VERSION 5.7 ;
BUSBITCHARS "[]" ;
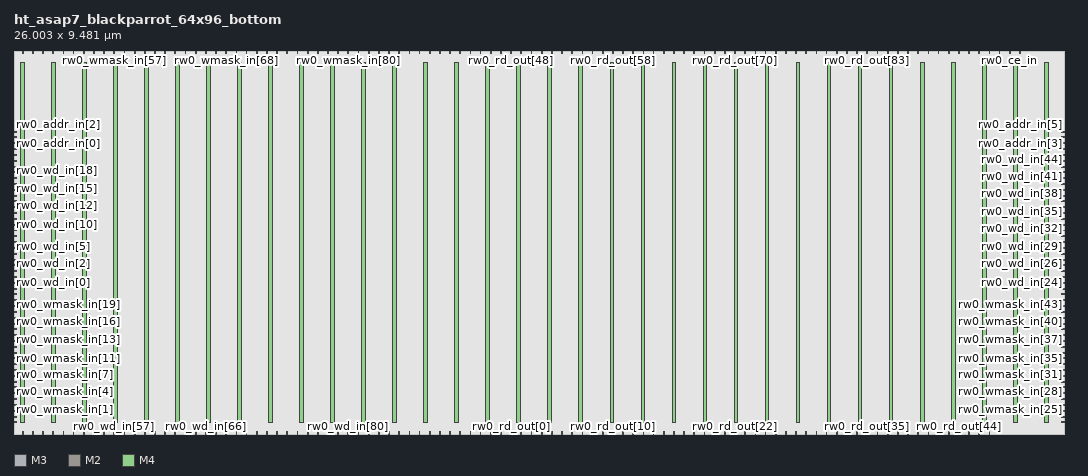
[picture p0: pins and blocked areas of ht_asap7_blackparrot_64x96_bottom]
MACRO ht_asap7_blackparrot_64x96_bottom
  FOREIGN ht_asap7_blackparrot_64x96_bottom 0 0 ;
  SYMMETRY X Y R90 ;
  SIZE 26.003 BY 9.481 ;
  CLASS COVER ;
  PIN rw0_wmask_in[0]
    DIRECTION INPUT ;
    USE SIGNAL ;
    SHAPE ABUTMENT ;
    PORT
      LAYER M3 ;
      RECT 0.000 0.276 0.072 0.300 ;
    END
  END rw0_wmask_in[0]
  PIN rw0_wmask_in[1]
    DIRECTION INPUT ;
    USE SIGNAL ;
    SHAPE ABUTMENT ;
    PORT
      LAYER M3 ;
      RECT 0.000 0.420 0.072 0.444 ;
    END
  END rw0_wmask_in[1]
  PIN rw0_wmask_in[2]
    DIRECTION INPUT ;
    USE SIGNAL ;
    SHAPE ABUTMENT ;
    PORT
      LAYER M3 ;
      RECT 0.000 0.564 0.072 0.588 ;
    END
  END rw0_wmask_in[2]
  PIN rw0_wmask_in[3]
    DIRECTION INPUT ;
    USE SIGNAL ;
    SHAPE ABUTMENT ;
    PORT
      LAYER M3 ;
      RECT 0.000 0.708 0.072 0.732 ;
    END
  END rw0_wmask_in[3]
  PIN rw0_wmask_in[4]
    DIRECTION INPUT ;
    USE SIGNAL ;
    SHAPE ABUTMENT ;
    PORT
      LAYER M3 ;
      RECT 0.000 0.852 0.072 0.876 ;
    END
  END rw0_wmask_in[4]
  PIN rw0_wmask_in[5]
    DIRECTION INPUT ;
    USE SIGNAL ;
    SHAPE ABUTMENT ;
    PORT
      LAYER M3 ;
      RECT 0.000 0.996 0.072 1.020 ;
    END
  END rw0_wmask_in[5]
  PIN rw0_wmask_in[6]
    DIRECTION INPUT ;
    USE SIGNAL ;
    SHAPE ABUTMENT ;
    PORT
      LAYER M3 ;
      RECT 0.000 1.140 0.072 1.164 ;
    END
  END rw0_wmask_in[6]
  PIN rw0_wmask_in[7]
    DIRECTION INPUT ;
    USE SIGNAL ;
    SHAPE ABUTMENT ;
    PORT
      LAYER M3 ;
      RECT 0.000 1.284 0.072 1.308 ;
    END
  END rw0_wmask_in[7]
  PIN rw0_wmask_in[8]
    DIRECTION INPUT ;
    USE SIGNAL ;
    SHAPE ABUTMENT ;
    PORT
      LAYER M3 ;
      RECT 0.000 1.428 0.072 1.452 ;
    END
  END rw0_wmask_in[8]
  PIN rw0_wmask_in[9]
    DIRECTION INPUT ;
    USE SIGNAL ;
    SHAPE ABUTMENT ;
    PORT
      LAYER M3 ;
      RECT 0.000 1.572 0.072 1.596 ;
    END
  END rw0_wmask_in[9]
  PIN rw0_wmask_in[10]
    DIRECTION INPUT ;
    USE SIGNAL ;
    SHAPE ABUTMENT ;
    PORT
      LAYER M3 ;
      RECT 0.000 1.716 0.072 1.740 ;
    END
  END rw0_wmask_in[10]
  PIN rw0_wmask_in[11]
    DIRECTION INPUT ;
    USE SIGNAL ;
    SHAPE ABUTMENT ;
    PORT
      LAYER M3 ;
      RECT 0.000 1.860 0.072 1.884 ;
    END
  END rw0_wmask_in[11]
  PIN rw0_wmask_in[12]
    DIRECTION INPUT ;
    USE SIGNAL ;
    SHAPE ABUTMENT ;
    PORT
      LAYER M3 ;
      RECT 0.000 2.004 0.072 2.028 ;
    END
  END rw0_wmask_in[12]
  PIN rw0_wmask_in[13]
    DIRECTION INPUT ;
    USE SIGNAL ;
    SHAPE ABUTMENT ;
    PORT
      LAYER M3 ;
      RECT 0.000 2.148 0.072 2.172 ;
    END
  END rw0_wmask_in[13]
  PIN rw0_wmask_in[14]
    DIRECTION INPUT ;
    USE SIGNAL ;
    SHAPE ABUTMENT ;
    PORT
      LAYER M3 ;
      RECT 0.000 2.292 0.072 2.316 ;
    END
  END rw0_wmask_in[14]
  PIN rw0_wmask_in[15]
    DIRECTION INPUT ;
    USE SIGNAL ;
    SHAPE ABUTMENT ;
    PORT
      LAYER M3 ;
      RECT 0.000 2.436 0.072 2.460 ;
    END
  END rw0_wmask_in[15]
  PIN rw0_wmask_in[16]
    DIRECTION INPUT ;
    USE SIGNAL ;
    SHAPE ABUTMENT ;
    PORT
      LAYER M3 ;
      RECT 0.000 2.580 0.072 2.604 ;
    END
  END rw0_wmask_in[16]
  PIN rw0_wmask_in[17]
    DIRECTION INPUT ;
    USE SIGNAL ;
    SHAPE ABUTMENT ;
    PORT
      LAYER M3 ;
      RECT 0.000 2.724 0.072 2.748 ;
    END
  END rw0_wmask_in[17]
  PIN rw0_wmask_in[18]
    DIRECTION INPUT ;
    USE SIGNAL ;
    SHAPE ABUTMENT ;
    PORT
      LAYER M3 ;
      RECT 0.000 2.868 0.072 2.892 ;
    END
  END rw0_wmask_in[18]
  PIN rw0_wmask_in[19]
    DIRECTION INPUT ;
    USE SIGNAL ;
    SHAPE ABUTMENT ;
    PORT
      LAYER M3 ;
      RECT 0.000 3.012 0.072 3.036 ;
    END
  END rw0_wmask_in[19]
  PIN rw0_wmask_in[20]
    DIRECTION INPUT ;
    USE SIGNAL ;
    SHAPE ABUTMENT ;
    PORT
      LAYER M3 ;
      RECT 0.000 3.156 0.072 3.180 ;
    END
  END rw0_wmask_in[20]
  PIN rw0_wmask_in[21]
    DIRECTION INPUT ;
    USE SIGNAL ;
    SHAPE ABUTMENT ;
    PORT
      LAYER M3 ;
      RECT 0.000 3.300 0.072 3.324 ;
    END
  END rw0_wmask_in[21]
  PIN rw0_wmask_in[22]
    DIRECTION INPUT ;
    USE SIGNAL ;
    SHAPE ABUTMENT ;
    PORT
      LAYER M3 ;
      RECT 0.000 3.444 0.072 3.468 ;
    END
  END rw0_wmask_in[22]
  PIN rw0_wmask_in[23]
    DIRECTION INPUT ;
    USE SIGNAL ;
    SHAPE ABUTMENT ;
    PORT
      LAYER M3 ;
      RECT 0.000 3.588 0.072 3.612 ;
    END
  END rw0_wmask_in[23]
  PIN rw0_wmask_in[24]
    DIRECTION INPUT ;
    USE SIGNAL ;
    SHAPE ABUTMENT ;
    PORT
      LAYER M3 ;
      RECT 25.931 0.276 26.003 0.300 ;
    END
  END rw0_wmask_in[24]
  PIN rw0_wmask_in[25]
    DIRECTION INPUT ;
    USE SIGNAL ;
    SHAPE ABUTMENT ;
    PORT
      LAYER M3 ;
      RECT 25.931 0.420 26.003 0.444 ;
    END
  END rw0_wmask_in[25]
  PIN rw0_wmask_in[26]
    DIRECTION INPUT ;
    USE SIGNAL ;
    SHAPE ABUTMENT ;
    PORT
      LAYER M3 ;
      RECT 25.931 0.564 26.003 0.588 ;
    END
  END rw0_wmask_in[26]
  PIN rw0_wmask_in[27]
    DIRECTION INPUT ;
    USE SIGNAL ;
    SHAPE ABUTMENT ;
    PORT
      LAYER M3 ;
      RECT 25.931 0.708 26.003 0.732 ;
    END
  END rw0_wmask_in[27]
  PIN rw0_wmask_in[28]
    DIRECTION INPUT ;
    USE SIGNAL ;
    SHAPE ABUTMENT ;
    PORT
      LAYER M3 ;
      RECT 25.931 0.852 26.003 0.876 ;
    END
  END rw0_wmask_in[28]
  PIN rw0_wmask_in[29]
    DIRECTION INPUT ;
    USE SIGNAL ;
    SHAPE ABUTMENT ;
    PORT
      LAYER M3 ;
      RECT 25.931 0.996 26.003 1.020 ;
    END
  END rw0_wmask_in[29]
  PIN rw0_wmask_in[30]
    DIRECTION INPUT ;
    USE SIGNAL ;
    SHAPE ABUTMENT ;
    PORT
      LAYER M3 ;
      RECT 25.931 1.140 26.003 1.164 ;
    END
  END rw0_wmask_in[30]
  PIN rw0_wmask_in[31]
    DIRECTION INPUT ;
    USE SIGNAL ;
    SHAPE ABUTMENT ;
    PORT
      LAYER M3 ;
      RECT 25.931 1.284 26.003 1.308 ;
    END
  END rw0_wmask_in[31]
  PIN rw0_wmask_in[32]
    DIRECTION INPUT ;
    USE SIGNAL ;
    SHAPE ABUTMENT ;
    PORT
      LAYER M3 ;
      RECT 25.931 1.428 26.003 1.452 ;
    END
  END rw0_wmask_in[32]
  PIN rw0_wmask_in[33]
    DIRECTION INPUT ;
    USE SIGNAL ;
    SHAPE ABUTMENT ;
    PORT
      LAYER M3 ;
      RECT 25.931 1.572 26.003 1.596 ;
    END
  END rw0_wmask_in[33]
  PIN rw0_wmask_in[34]
    DIRECTION INPUT ;
    USE SIGNAL ;
    SHAPE ABUTMENT ;
    PORT
      LAYER M3 ;
      RECT 25.931 1.716 26.003 1.740 ;
    END
  END rw0_wmask_in[34]
  PIN rw0_wmask_in[35]
    DIRECTION INPUT ;
    USE SIGNAL ;
    SHAPE ABUTMENT ;
    PORT
      LAYER M3 ;
      RECT 25.931 1.860 26.003 1.884 ;
    END
  END rw0_wmask_in[35]
  PIN rw0_wmask_in[36]
    DIRECTION INPUT ;
    USE SIGNAL ;
    SHAPE ABUTMENT ;
    PORT
      LAYER M3 ;
      RECT 25.931 2.004 26.003 2.028 ;
    END
  END rw0_wmask_in[36]
  PIN rw0_wmask_in[37]
    DIRECTION INPUT ;
    USE SIGNAL ;
    SHAPE ABUTMENT ;
    PORT
      LAYER M3 ;
      RECT 25.931 2.148 26.003 2.172 ;
    END
  END rw0_wmask_in[37]
  PIN rw0_wmask_in[38]
    DIRECTION INPUT ;
    USE SIGNAL ;
    SHAPE ABUTMENT ;
    PORT
      LAYER M3 ;
      RECT 25.931 2.292 26.003 2.316 ;
    END
  END rw0_wmask_in[38]
  PIN rw0_wmask_in[39]
    DIRECTION INPUT ;
    USE SIGNAL ;
    SHAPE ABUTMENT ;
    PORT
      LAYER M3 ;
      RECT 25.931 2.436 26.003 2.460 ;
    END
  END rw0_wmask_in[39]
  PIN rw0_wmask_in[40]
    DIRECTION INPUT ;
    USE SIGNAL ;
    SHAPE ABUTMENT ;
    PORT
      LAYER M3 ;
      RECT 25.931 2.580 26.003 2.604 ;
    END
  END rw0_wmask_in[40]
  PIN rw0_wmask_in[41]
    DIRECTION INPUT ;
    USE SIGNAL ;
    SHAPE ABUTMENT ;
    PORT
      LAYER M3 ;
      RECT 25.931 2.724 26.003 2.748 ;
    END
  END rw0_wmask_in[41]
  PIN rw0_wmask_in[42]
    DIRECTION INPUT ;
    USE SIGNAL ;
    SHAPE ABUTMENT ;
    PORT
      LAYER M3 ;
      RECT 25.931 2.868 26.003 2.892 ;
    END
  END rw0_wmask_in[42]
  PIN rw0_wmask_in[43]
    DIRECTION INPUT ;
    USE SIGNAL ;
    SHAPE ABUTMENT ;
    PORT
      LAYER M3 ;
      RECT 25.931 3.012 26.003 3.036 ;
    END
  END rw0_wmask_in[43]
  PIN rw0_wmask_in[44]
    DIRECTION INPUT ;
    USE SIGNAL ;
    SHAPE ABUTMENT ;
    PORT
      LAYER M3 ;
      RECT 25.931 3.156 26.003 3.180 ;
    END
  END rw0_wmask_in[44]
  PIN rw0_wmask_in[45]
    DIRECTION INPUT ;
    USE SIGNAL ;
    SHAPE ABUTMENT ;
    PORT
      LAYER M3 ;
      RECT 25.931 3.300 26.003 3.324 ;
    END
  END rw0_wmask_in[45]
  PIN rw0_wmask_in[46]
    DIRECTION INPUT ;
    USE SIGNAL ;
    SHAPE ABUTMENT ;
    PORT
      LAYER M3 ;
      RECT 25.931 3.444 26.003 3.468 ;
    END
  END rw0_wmask_in[46]
  PIN rw0_wmask_in[47]
    DIRECTION INPUT ;
    USE SIGNAL ;
    SHAPE ABUTMENT ;
    PORT
      LAYER M3 ;
      RECT 25.931 3.588 26.003 3.612 ;
    END
  END rw0_wmask_in[47]
  PIN rw0_wmask_in[48]
    DIRECTION INPUT ;
    USE SIGNAL ;
    SHAPE ABUTMENT ;
    PORT
      LAYER M2 ;
      RECT 0.207 9.427 0.225 9.481 ;
    END
  END rw0_wmask_in[48]
  PIN rw0_wmask_in[49]
    DIRECTION INPUT ;
    USE SIGNAL ;
    SHAPE ABUTMENT ;
    PORT
      LAYER M2 ;
      RECT 0.459 9.427 0.477 9.481 ;
    END
  END rw0_wmask_in[49]
  PIN rw0_wmask_in[50]
    DIRECTION INPUT ;
    USE SIGNAL ;
    SHAPE ABUTMENT ;
    PORT
      LAYER M2 ;
      RECT 0.711 9.427 0.729 9.481 ;
    END
  END rw0_wmask_in[50]
  PIN rw0_wmask_in[51]
    DIRECTION INPUT ;
    USE SIGNAL ;
    SHAPE ABUTMENT ;
    PORT
      LAYER M2 ;
      RECT 0.963 9.427 0.981 9.481 ;
    END
  END rw0_wmask_in[51]
  PIN rw0_wmask_in[52]
    DIRECTION INPUT ;
    USE SIGNAL ;
    SHAPE ABUTMENT ;
    PORT
      LAYER M2 ;
      RECT 1.215 9.427 1.233 9.481 ;
    END
  END rw0_wmask_in[52]
  PIN rw0_wmask_in[53]
    DIRECTION INPUT ;
    USE SIGNAL ;
    SHAPE ABUTMENT ;
    PORT
      LAYER M2 ;
      RECT 1.467 9.427 1.485 9.481 ;
    END
  END rw0_wmask_in[53]
  PIN rw0_wmask_in[54]
    DIRECTION INPUT ;
    USE SIGNAL ;
    SHAPE ABUTMENT ;
    PORT
      LAYER M2 ;
      RECT 1.719 9.427 1.737 9.481 ;
    END
  END rw0_wmask_in[54]
  PIN rw0_wmask_in[55]
    DIRECTION INPUT ;
    USE SIGNAL ;
    SHAPE ABUTMENT ;
    PORT
      LAYER M2 ;
      RECT 1.971 9.427 1.989 9.481 ;
    END
  END rw0_wmask_in[55]
  PIN rw0_wmask_in[56]
    DIRECTION INPUT ;
    USE SIGNAL ;
    SHAPE ABUTMENT ;
    PORT
      LAYER M2 ;
      RECT 2.223 9.427 2.241 9.481 ;
    END
  END rw0_wmask_in[56]
  PIN rw0_wmask_in[57]
    DIRECTION INPUT ;
    USE SIGNAL ;
    SHAPE ABUTMENT ;
    PORT
      LAYER M2 ;
      RECT 2.475 9.427 2.493 9.481 ;
    END
  END rw0_wmask_in[57]
  PIN rw0_wmask_in[58]
    DIRECTION INPUT ;
    USE SIGNAL ;
    SHAPE ABUTMENT ;
    PORT
      LAYER M2 ;
      RECT 2.727 9.427 2.745 9.481 ;
    END
  END rw0_wmask_in[58]
  PIN rw0_wmask_in[59]
    DIRECTION INPUT ;
    USE SIGNAL ;
    SHAPE ABUTMENT ;
    PORT
      LAYER M2 ;
      RECT 2.979 9.427 2.997 9.481 ;
    END
  END rw0_wmask_in[59]
  PIN rw0_wmask_in[60]
    DIRECTION INPUT ;
    USE SIGNAL ;
    SHAPE ABUTMENT ;
    PORT
      LAYER M2 ;
      RECT 3.231 9.427 3.249 9.481 ;
    END
  END rw0_wmask_in[60]
  PIN rw0_wmask_in[61]
    DIRECTION INPUT ;
    USE SIGNAL ;
    SHAPE ABUTMENT ;
    PORT
      LAYER M2 ;
      RECT 3.483 9.427 3.501 9.481 ;
    END
  END rw0_wmask_in[61]
  PIN rw0_wmask_in[62]
    DIRECTION INPUT ;
    USE SIGNAL ;
    SHAPE ABUTMENT ;
    PORT
      LAYER M2 ;
      RECT 3.735 9.427 3.753 9.481 ;
    END
  END rw0_wmask_in[62]
  PIN rw0_wmask_in[63]
    DIRECTION INPUT ;
    USE SIGNAL ;
    SHAPE ABUTMENT ;
    PORT
      LAYER M2 ;
      RECT 3.987 9.427 4.005 9.481 ;
    END
  END rw0_wmask_in[63]
  PIN rw0_wmask_in[64]
    DIRECTION INPUT ;
    USE SIGNAL ;
    SHAPE ABUTMENT ;
    PORT
      LAYER M2 ;
      RECT 4.239 9.427 4.257 9.481 ;
    END
  END rw0_wmask_in[64]
  PIN rw0_wmask_in[65]
    DIRECTION INPUT ;
    USE SIGNAL ;
    SHAPE ABUTMENT ;
    PORT
      LAYER M2 ;
      RECT 4.491 9.427 4.509 9.481 ;
    END
  END rw0_wmask_in[65]
  PIN rw0_wmask_in[66]
    DIRECTION INPUT ;
    USE SIGNAL ;
    SHAPE ABUTMENT ;
    PORT
      LAYER M2 ;
      RECT 4.743 9.427 4.761 9.481 ;
    END
  END rw0_wmask_in[66]
  PIN rw0_wmask_in[67]
    DIRECTION INPUT ;
    USE SIGNAL ;
    SHAPE ABUTMENT ;
    PORT
      LAYER M2 ;
      RECT 4.995 9.427 5.013 9.481 ;
    END
  END rw0_wmask_in[67]
  PIN rw0_wmask_in[68]
    DIRECTION INPUT ;
    USE SIGNAL ;
    SHAPE ABUTMENT ;
    PORT
      LAYER M2 ;
      RECT 5.247 9.427 5.265 9.481 ;
    END
  END rw0_wmask_in[68]
  PIN rw0_wmask_in[69]
    DIRECTION INPUT ;
    USE SIGNAL ;
    SHAPE ABUTMENT ;
    PORT
      LAYER M2 ;
      RECT 5.499 9.427 5.517 9.481 ;
    END
  END rw0_wmask_in[69]
  PIN rw0_wmask_in[70]
    DIRECTION INPUT ;
    USE SIGNAL ;
    SHAPE ABUTMENT ;
    PORT
      LAYER M2 ;
      RECT 5.751 9.427 5.769 9.481 ;
    END
  END rw0_wmask_in[70]
  PIN rw0_wmask_in[71]
    DIRECTION INPUT ;
    USE SIGNAL ;
    SHAPE ABUTMENT ;
    PORT
      LAYER M2 ;
      RECT 6.003 9.427 6.021 9.481 ;
    END
  END rw0_wmask_in[71]
  PIN rw0_wmask_in[72]
    DIRECTION INPUT ;
    USE SIGNAL ;
    SHAPE ABUTMENT ;
    PORT
      LAYER M2 ;
      RECT 6.255 9.427 6.273 9.481 ;
    END
  END rw0_wmask_in[72]
  PIN rw0_wmask_in[73]
    DIRECTION INPUT ;
    USE SIGNAL ;
    SHAPE ABUTMENT ;
    PORT
      LAYER M2 ;
      RECT 6.507 9.427 6.525 9.481 ;
    END
  END rw0_wmask_in[73]
  PIN rw0_wmask_in[74]
    DIRECTION INPUT ;
    USE SIGNAL ;
    SHAPE ABUTMENT ;
    PORT
      LAYER M2 ;
      RECT 6.759 9.427 6.777 9.481 ;
    END
  END rw0_wmask_in[74]
  PIN rw0_wmask_in[75]
    DIRECTION INPUT ;
    USE SIGNAL ;
    SHAPE ABUTMENT ;
    PORT
      LAYER M2 ;
      RECT 7.011 9.427 7.029 9.481 ;
    END
  END rw0_wmask_in[75]
  PIN rw0_wmask_in[76]
    DIRECTION INPUT ;
    USE SIGNAL ;
    SHAPE ABUTMENT ;
    PORT
      LAYER M2 ;
      RECT 7.263 9.427 7.281 9.481 ;
    END
  END rw0_wmask_in[76]
  PIN rw0_wmask_in[77]
    DIRECTION INPUT ;
    USE SIGNAL ;
    SHAPE ABUTMENT ;
    PORT
      LAYER M2 ;
      RECT 7.515 9.427 7.533 9.481 ;
    END
  END rw0_wmask_in[77]
  PIN rw0_wmask_in[78]
    DIRECTION INPUT ;
    USE SIGNAL ;
    SHAPE ABUTMENT ;
    PORT
      LAYER M2 ;
      RECT 7.767 9.427 7.785 9.481 ;
    END
  END rw0_wmask_in[78]
  PIN rw0_wmask_in[79]
    DIRECTION INPUT ;
    USE SIGNAL ;
    SHAPE ABUTMENT ;
    PORT
      LAYER M2 ;
      RECT 8.019 9.427 8.037 9.481 ;
    END
  END rw0_wmask_in[79]
  PIN rw0_wmask_in[80]
    DIRECTION INPUT ;
    USE SIGNAL ;
    SHAPE ABUTMENT ;
    PORT
      LAYER M2 ;
      RECT 8.271 9.427 8.289 9.481 ;
    END
  END rw0_wmask_in[80]
  PIN rw0_wmask_in[81]
    DIRECTION INPUT ;
    USE SIGNAL ;
    SHAPE ABUTMENT ;
    PORT
      LAYER M2 ;
      RECT 8.523 9.427 8.541 9.481 ;
    END
  END rw0_wmask_in[81]
  PIN rw0_wmask_in[82]
    DIRECTION INPUT ;
    USE SIGNAL ;
    SHAPE ABUTMENT ;
    PORT
      LAYER M2 ;
      RECT 8.775 9.427 8.793 9.481 ;
    END
  END rw0_wmask_in[82]
  PIN rw0_wmask_in[83]
    DIRECTION INPUT ;
    USE SIGNAL ;
    SHAPE ABUTMENT ;
    PORT
      LAYER M2 ;
      RECT 9.027 9.427 9.045 9.481 ;
    END
  END rw0_wmask_in[83]
  PIN rw0_wmask_in[84]
    DIRECTION INPUT ;
    USE SIGNAL ;
    SHAPE ABUTMENT ;
    PORT
      LAYER M2 ;
      RECT 9.279 9.427 9.297 9.481 ;
    END
  END rw0_wmask_in[84]
  PIN rw0_wmask_in[85]
    DIRECTION INPUT ;
    USE SIGNAL ;
    SHAPE ABUTMENT ;
    PORT
      LAYER M2 ;
      RECT 9.531 9.427 9.549 9.481 ;
    END
  END rw0_wmask_in[85]
  PIN rw0_wmask_in[86]
    DIRECTION INPUT ;
    USE SIGNAL ;
    SHAPE ABUTMENT ;
    PORT
      LAYER M2 ;
      RECT 9.783 9.427 9.801 9.481 ;
    END
  END rw0_wmask_in[86]
  PIN rw0_wmask_in[87]
    DIRECTION INPUT ;
    USE SIGNAL ;
    SHAPE ABUTMENT ;
    PORT
      LAYER M2 ;
      RECT 10.035 9.427 10.053 9.481 ;
    END
  END rw0_wmask_in[87]
  PIN rw0_wmask_in[88]
    DIRECTION INPUT ;
    USE SIGNAL ;
    SHAPE ABUTMENT ;
    PORT
      LAYER M2 ;
      RECT 10.287 9.427 10.305 9.481 ;
    END
  END rw0_wmask_in[88]
  PIN rw0_wmask_in[89]
    DIRECTION INPUT ;
    USE SIGNAL ;
    SHAPE ABUTMENT ;
    PORT
      LAYER M2 ;
      RECT 10.539 9.427 10.557 9.481 ;
    END
  END rw0_wmask_in[89]
  PIN rw0_wmask_in[90]
    DIRECTION INPUT ;
    USE SIGNAL ;
    SHAPE ABUTMENT ;
    PORT
      LAYER M2 ;
      RECT 10.791 9.427 10.809 9.481 ;
    END
  END rw0_wmask_in[90]
  PIN rw0_wmask_in[91]
    DIRECTION INPUT ;
    USE SIGNAL ;
    SHAPE ABUTMENT ;
    PORT
      LAYER M2 ;
      RECT 11.043 9.427 11.061 9.481 ;
    END
  END rw0_wmask_in[91]
  PIN rw0_wmask_in[92]
    DIRECTION INPUT ;
    USE SIGNAL ;
    SHAPE ABUTMENT ;
    PORT
      LAYER M2 ;
      RECT 11.295 9.427 11.313 9.481 ;
    END
  END rw0_wmask_in[92]
  PIN rw0_wmask_in[93]
    DIRECTION INPUT ;
    USE SIGNAL ;
    SHAPE ABUTMENT ;
    PORT
      LAYER M2 ;
      RECT 11.547 9.427 11.565 9.481 ;
    END
  END rw0_wmask_in[93]
  PIN rw0_wmask_in[94]
    DIRECTION INPUT ;
    USE SIGNAL ;
    SHAPE ABUTMENT ;
    PORT
      LAYER M2 ;
      RECT 11.799 9.427 11.817 9.481 ;
    END
  END rw0_wmask_in[94]
  PIN rw0_wmask_in[95]
    DIRECTION INPUT ;
    USE SIGNAL ;
    SHAPE ABUTMENT ;
    PORT
      LAYER M2 ;
      RECT 12.051 9.427 12.069 9.481 ;
    END
  END rw0_wmask_in[95]
  PIN rw0_wd_in[0]
    DIRECTION INPUT ;
    USE SIGNAL ;
    SHAPE ABUTMENT ;
    PORT
      LAYER M3 ;
      RECT 0.000 3.732 0.072 3.756 ;
    END
  END rw0_wd_in[0]
  PIN rw0_wd_in[1]
    DIRECTION INPUT ;
    USE SIGNAL ;
    SHAPE ABUTMENT ;
    PORT
      LAYER M3 ;
      RECT 0.000 3.876 0.072 3.900 ;
    END
  END rw0_wd_in[1]
  PIN rw0_wd_in[2]
    DIRECTION INPUT ;
    USE SIGNAL ;
    SHAPE ABUTMENT ;
    PORT
      LAYER M3 ;
      RECT 0.000 4.020 0.072 4.044 ;
    END
  END rw0_wd_in[2]
  PIN rw0_wd_in[3]
    DIRECTION INPUT ;
    USE SIGNAL ;
    SHAPE ABUTMENT ;
    PORT
      LAYER M3 ;
      RECT 0.000 4.164 0.072 4.188 ;
    END
  END rw0_wd_in[3]
  PIN rw0_wd_in[4]
    DIRECTION INPUT ;
    USE SIGNAL ;
    SHAPE ABUTMENT ;
    PORT
      LAYER M3 ;
      RECT 0.000 4.308 0.072 4.332 ;
    END
  END rw0_wd_in[4]
  PIN rw0_wd_in[5]
    DIRECTION INPUT ;
    USE SIGNAL ;
    SHAPE ABUTMENT ;
    PORT
      LAYER M3 ;
      RECT 0.000 4.452 0.072 4.476 ;
    END
  END rw0_wd_in[5]
  PIN rw0_wd_in[6]
    DIRECTION INPUT ;
    USE SIGNAL ;
    SHAPE ABUTMENT ;
    PORT
      LAYER M3 ;
      RECT 0.000 4.596 0.072 4.620 ;
    END
  END rw0_wd_in[6]
  PIN rw0_wd_in[7]
    DIRECTION INPUT ;
    USE SIGNAL ;
    SHAPE ABUTMENT ;
    PORT
      LAYER M3 ;
      RECT 0.000 4.740 0.072 4.764 ;
    END
  END rw0_wd_in[7]
  PIN rw0_wd_in[8]
    DIRECTION INPUT ;
    USE SIGNAL ;
    SHAPE ABUTMENT ;
    PORT
      LAYER M3 ;
      RECT 0.000 4.884 0.072 4.908 ;
    END
  END rw0_wd_in[8]
  PIN rw0_wd_in[9]
    DIRECTION INPUT ;
    USE SIGNAL ;
    SHAPE ABUTMENT ;
    PORT
      LAYER M3 ;
      RECT 0.000 5.028 0.072 5.052 ;
    END
  END rw0_wd_in[9]
  PIN rw0_wd_in[10]
    DIRECTION INPUT ;
    USE SIGNAL ;
    SHAPE ABUTMENT ;
    PORT
      LAYER M3 ;
      RECT 0.000 5.172 0.072 5.196 ;
    END
  END rw0_wd_in[10]
  PIN rw0_wd_in[11]
    DIRECTION INPUT ;
    USE SIGNAL ;
    SHAPE ABUTMENT ;
    PORT
      LAYER M3 ;
      RECT 0.000 5.316 0.072 5.340 ;
    END
  END rw0_wd_in[11]
  PIN rw0_wd_in[12]
    DIRECTION INPUT ;
    USE SIGNAL ;
    SHAPE ABUTMENT ;
    PORT
      LAYER M3 ;
      RECT 0.000 5.460 0.072 5.484 ;
    END
  END rw0_wd_in[12]
  PIN rw0_wd_in[13]
    DIRECTION INPUT ;
    USE SIGNAL ;
    SHAPE ABUTMENT ;
    PORT
      LAYER M3 ;
      RECT 0.000 5.604 0.072 5.628 ;
    END
  END rw0_wd_in[13]
  PIN rw0_wd_in[14]
    DIRECTION INPUT ;
    USE SIGNAL ;
    SHAPE ABUTMENT ;
    PORT
      LAYER M3 ;
      RECT 0.000 5.748 0.072 5.772 ;
    END
  END rw0_wd_in[14]
  PIN rw0_wd_in[15]
    DIRECTION INPUT ;
    USE SIGNAL ;
    SHAPE ABUTMENT ;
    PORT
      LAYER M3 ;
      RECT 0.000 5.892 0.072 5.916 ;
    END
  END rw0_wd_in[15]
  PIN rw0_wd_in[16]
    DIRECTION INPUT ;
    USE SIGNAL ;
    SHAPE ABUTMENT ;
    PORT
      LAYER M3 ;
      RECT 0.000 6.036 0.072 6.060 ;
    END
  END rw0_wd_in[16]
  PIN rw0_wd_in[17]
    DIRECTION INPUT ;
    USE SIGNAL ;
    SHAPE ABUTMENT ;
    PORT
      LAYER M3 ;
      RECT 0.000 6.180 0.072 6.204 ;
    END
  END rw0_wd_in[17]
  PIN rw0_wd_in[18]
    DIRECTION INPUT ;
    USE SIGNAL ;
    SHAPE ABUTMENT ;
    PORT
      LAYER M3 ;
      RECT 0.000 6.324 0.072 6.348 ;
    END
  END rw0_wd_in[18]
  PIN rw0_wd_in[19]
    DIRECTION INPUT ;
    USE SIGNAL ;
    SHAPE ABUTMENT ;
    PORT
      LAYER M3 ;
      RECT 0.000 6.468 0.072 6.492 ;
    END
  END rw0_wd_in[19]
  PIN rw0_wd_in[20]
    DIRECTION INPUT ;
    USE SIGNAL ;
    SHAPE ABUTMENT ;
    PORT
      LAYER M3 ;
      RECT 0.000 6.612 0.072 6.636 ;
    END
  END rw0_wd_in[20]
  PIN rw0_wd_in[21]
    DIRECTION INPUT ;
    USE SIGNAL ;
    SHAPE ABUTMENT ;
    PORT
      LAYER M3 ;
      RECT 0.000 6.756 0.072 6.780 ;
    END
  END rw0_wd_in[21]
  PIN rw0_wd_in[22]
    DIRECTION INPUT ;
    USE SIGNAL ;
    SHAPE ABUTMENT ;
    PORT
      LAYER M3 ;
      RECT 0.000 6.900 0.072 6.924 ;
    END
  END rw0_wd_in[22]
  PIN rw0_wd_in[23]
    DIRECTION INPUT ;
    USE SIGNAL ;
    SHAPE ABUTMENT ;
    PORT
      LAYER M3 ;
      RECT 0.000 7.044 0.072 7.068 ;
    END
  END rw0_wd_in[23]
  PIN rw0_wd_in[24]
    DIRECTION INPUT ;
    USE SIGNAL ;
    SHAPE ABUTMENT ;
    PORT
      LAYER M3 ;
      RECT 25.931 3.732 26.003 3.756 ;
    END
  END rw0_wd_in[24]
  PIN rw0_wd_in[25]
    DIRECTION INPUT ;
    USE SIGNAL ;
    SHAPE ABUTMENT ;
    PORT
      LAYER M3 ;
      RECT 25.931 3.876 26.003 3.900 ;
    END
  END rw0_wd_in[25]
  PIN rw0_wd_in[26]
    DIRECTION INPUT ;
    USE SIGNAL ;
    SHAPE ABUTMENT ;
    PORT
      LAYER M3 ;
      RECT 25.931 4.020 26.003 4.044 ;
    END
  END rw0_wd_in[26]
  PIN rw0_wd_in[27]
    DIRECTION INPUT ;
    USE SIGNAL ;
    SHAPE ABUTMENT ;
    PORT
      LAYER M3 ;
      RECT 25.931 4.164 26.003 4.188 ;
    END
  END rw0_wd_in[27]
  PIN rw0_wd_in[28]
    DIRECTION INPUT ;
    USE SIGNAL ;
    SHAPE ABUTMENT ;
    PORT
      LAYER M3 ;
      RECT 25.931 4.308 26.003 4.332 ;
    END
  END rw0_wd_in[28]
  PIN rw0_wd_in[29]
    DIRECTION INPUT ;
    USE SIGNAL ;
    SHAPE ABUTMENT ;
    PORT
      LAYER M3 ;
      RECT 25.931 4.452 26.003 4.476 ;
    END
  END rw0_wd_in[29]
  PIN rw0_wd_in[30]
    DIRECTION INPUT ;
    USE SIGNAL ;
    SHAPE ABUTMENT ;
    PORT
      LAYER M3 ;
      RECT 25.931 4.596 26.003 4.620 ;
    END
  END rw0_wd_in[30]
  PIN rw0_wd_in[31]
    DIRECTION INPUT ;
    USE SIGNAL ;
    SHAPE ABUTMENT ;
    PORT
      LAYER M3 ;
      RECT 25.931 4.740 26.003 4.764 ;
    END
  END rw0_wd_in[31]
  PIN rw0_wd_in[32]
    DIRECTION INPUT ;
    USE SIGNAL ;
    SHAPE ABUTMENT ;
    PORT
      LAYER M3 ;
      RECT 25.931 4.884 26.003 4.908 ;
    END
  END rw0_wd_in[32]
  PIN rw0_wd_in[33]
    DIRECTION INPUT ;
    USE SIGNAL ;
    SHAPE ABUTMENT ;
    PORT
      LAYER M3 ;
      RECT 25.931 5.028 26.003 5.052 ;
    END
  END rw0_wd_in[33]
  PIN rw0_wd_in[34]
    DIRECTION INPUT ;
    USE SIGNAL ;
    SHAPE ABUTMENT ;
    PORT
      LAYER M3 ;
      RECT 25.931 5.172 26.003 5.196 ;
    END
  END rw0_wd_in[34]
  PIN rw0_wd_in[35]
    DIRECTION INPUT ;
    USE SIGNAL ;
    SHAPE ABUTMENT ;
    PORT
      LAYER M3 ;
      RECT 25.931 5.316 26.003 5.340 ;
    END
  END rw0_wd_in[35]
  PIN rw0_wd_in[36]
    DIRECTION INPUT ;
    USE SIGNAL ;
    SHAPE ABUTMENT ;
    PORT
      LAYER M3 ;
      RECT 25.931 5.460 26.003 5.484 ;
    END
  END rw0_wd_in[36]
  PIN rw0_wd_in[37]
    DIRECTION INPUT ;
    USE SIGNAL ;
    SHAPE ABUTMENT ;
    PORT
      LAYER M3 ;
      RECT 25.931 5.604 26.003 5.628 ;
    END
  END rw0_wd_in[37]
  PIN rw0_wd_in[38]
    DIRECTION INPUT ;
    USE SIGNAL ;
    SHAPE ABUTMENT ;
    PORT
      LAYER M3 ;
      RECT 25.931 5.748 26.003 5.772 ;
    END
  END rw0_wd_in[38]
  PIN rw0_wd_in[39]
    DIRECTION INPUT ;
    USE SIGNAL ;
    SHAPE ABUTMENT ;
    PORT
      LAYER M3 ;
      RECT 25.931 5.892 26.003 5.916 ;
    END
  END rw0_wd_in[39]
  PIN rw0_wd_in[40]
    DIRECTION INPUT ;
    USE SIGNAL ;
    SHAPE ABUTMENT ;
    PORT
      LAYER M3 ;
      RECT 25.931 6.036 26.003 6.060 ;
    END
  END rw0_wd_in[40]
  PIN rw0_wd_in[41]
    DIRECTION INPUT ;
    USE SIGNAL ;
    SHAPE ABUTMENT ;
    PORT
      LAYER M3 ;
      RECT 25.931 6.180 26.003 6.204 ;
    END
  END rw0_wd_in[41]
  PIN rw0_wd_in[42]
    DIRECTION INPUT ;
    USE SIGNAL ;
    SHAPE ABUTMENT ;
    PORT
      LAYER M3 ;
      RECT 25.931 6.324 26.003 6.348 ;
    END
  END rw0_wd_in[42]
  PIN rw0_wd_in[43]
    DIRECTION INPUT ;
    USE SIGNAL ;
    SHAPE ABUTMENT ;
    PORT
      LAYER M3 ;
      RECT 25.931 6.468 26.003 6.492 ;
    END
  END rw0_wd_in[43]
  PIN rw0_wd_in[44]
    DIRECTION INPUT ;
    USE SIGNAL ;
    SHAPE ABUTMENT ;
    PORT
      LAYER M3 ;
      RECT 25.931 6.612 26.003 6.636 ;
    END
  END rw0_wd_in[44]
  PIN rw0_wd_in[45]
    DIRECTION INPUT ;
    USE SIGNAL ;
    SHAPE ABUTMENT ;
    PORT
      LAYER M3 ;
      RECT 25.931 6.756 26.003 6.780 ;
    END
  END rw0_wd_in[45]
  PIN rw0_wd_in[46]
    DIRECTION INPUT ;
    USE SIGNAL ;
    SHAPE ABUTMENT ;
    PORT
      LAYER M3 ;
      RECT 25.931 6.900 26.003 6.924 ;
    END
  END rw0_wd_in[46]
  PIN rw0_wd_in[47]
    DIRECTION INPUT ;
    USE SIGNAL ;
    SHAPE ABUTMENT ;
    PORT
      LAYER M3 ;
      RECT 25.931 7.044 26.003 7.068 ;
    END
  END rw0_wd_in[47]
  PIN rw0_wd_in[48]
    DIRECTION INPUT ;
    USE SIGNAL ;
    SHAPE ABUTMENT ;
    PORT
      LAYER M2 ;
      RECT 0.207 0.000 0.225 0.054 ;
    END
  END rw0_wd_in[48]
  PIN rw0_wd_in[49]
    DIRECTION INPUT ;
    USE SIGNAL ;
    SHAPE ABUTMENT ;
    PORT
      LAYER M2 ;
      RECT 0.459 0.000 0.477 0.054 ;
    END
  END rw0_wd_in[49]
  PIN rw0_wd_in[50]
    DIRECTION INPUT ;
    USE SIGNAL ;
    SHAPE ABUTMENT ;
    PORT
      LAYER M2 ;
      RECT 0.711 0.000 0.729 0.054 ;
    END
  END rw0_wd_in[50]
  PIN rw0_wd_in[51]
    DIRECTION INPUT ;
    USE SIGNAL ;
    SHAPE ABUTMENT ;
    PORT
      LAYER M2 ;
      RECT 0.963 0.000 0.981 0.054 ;
    END
  END rw0_wd_in[51]
  PIN rw0_wd_in[52]
    DIRECTION INPUT ;
    USE SIGNAL ;
    SHAPE ABUTMENT ;
    PORT
      LAYER M2 ;
      RECT 1.215 0.000 1.233 0.054 ;
    END
  END rw0_wd_in[52]
  PIN rw0_wd_in[53]
    DIRECTION INPUT ;
    USE SIGNAL ;
    SHAPE ABUTMENT ;
    PORT
      LAYER M2 ;
      RECT 1.467 0.000 1.485 0.054 ;
    END
  END rw0_wd_in[53]
  PIN rw0_wd_in[54]
    DIRECTION INPUT ;
    USE SIGNAL ;
    SHAPE ABUTMENT ;
    PORT
      LAYER M2 ;
      RECT 1.719 0.000 1.737 0.054 ;
    END
  END rw0_wd_in[54]
  PIN rw0_wd_in[55]
    DIRECTION INPUT ;
    USE SIGNAL ;
    SHAPE ABUTMENT ;
    PORT
      LAYER M2 ;
      RECT 1.971 0.000 1.989 0.054 ;
    END
  END rw0_wd_in[55]
  PIN rw0_wd_in[56]
    DIRECTION INPUT ;
    USE SIGNAL ;
    SHAPE ABUTMENT ;
    PORT
      LAYER M2 ;
      RECT 2.223 0.000 2.241 0.054 ;
    END
  END rw0_wd_in[56]
  PIN rw0_wd_in[57]
    DIRECTION INPUT ;
    USE SIGNAL ;
    SHAPE ABUTMENT ;
    PORT
      LAYER M2 ;
      RECT 2.475 0.000 2.493 0.054 ;
    END
  END rw0_wd_in[57]
  PIN rw0_wd_in[58]
    DIRECTION INPUT ;
    USE SIGNAL ;
    SHAPE ABUTMENT ;
    PORT
      LAYER M2 ;
      RECT 2.727 0.000 2.745 0.054 ;
    END
  END rw0_wd_in[58]
  PIN rw0_wd_in[59]
    DIRECTION INPUT ;
    USE SIGNAL ;
    SHAPE ABUTMENT ;
    PORT
      LAYER M2 ;
      RECT 2.979 0.000 2.997 0.054 ;
    END
  END rw0_wd_in[59]
  PIN rw0_wd_in[60]
    DIRECTION INPUT ;
    USE SIGNAL ;
    SHAPE ABUTMENT ;
    PORT
      LAYER M2 ;
      RECT 3.231 0.000 3.249 0.054 ;
    END
  END rw0_wd_in[60]
  PIN rw0_wd_in[61]
    DIRECTION INPUT ;
    USE SIGNAL ;
    SHAPE ABUTMENT ;
    PORT
      LAYER M2 ;
      RECT 3.483 0.000 3.501 0.054 ;
    END
  END rw0_wd_in[61]
  PIN rw0_wd_in[62]
    DIRECTION INPUT ;
    USE SIGNAL ;
    SHAPE ABUTMENT ;
    PORT
      LAYER M2 ;
      RECT 3.735 0.000 3.753 0.054 ;
    END
  END rw0_wd_in[62]
  PIN rw0_wd_in[63]
    DIRECTION INPUT ;
    USE SIGNAL ;
    SHAPE ABUTMENT ;
    PORT
      LAYER M2 ;
      RECT 3.987 0.000 4.005 0.054 ;
    END
  END rw0_wd_in[63]
  PIN rw0_wd_in[64]
    DIRECTION INPUT ;
    USE SIGNAL ;
    SHAPE ABUTMENT ;
    PORT
      LAYER M2 ;
      RECT 4.239 0.000 4.257 0.054 ;
    END
  END rw0_wd_in[64]
  PIN rw0_wd_in[65]
    DIRECTION INPUT ;
    USE SIGNAL ;
    SHAPE ABUTMENT ;
    PORT
      LAYER M2 ;
      RECT 4.491 0.000 4.509 0.054 ;
    END
  END rw0_wd_in[65]
  PIN rw0_wd_in[66]
    DIRECTION INPUT ;
    USE SIGNAL ;
    SHAPE ABUTMENT ;
    PORT
      LAYER M2 ;
      RECT 4.743 0.000 4.761 0.054 ;
    END
  END rw0_wd_in[66]
  PIN rw0_wd_in[67]
    DIRECTION INPUT ;
    USE SIGNAL ;
    SHAPE ABUTMENT ;
    PORT
      LAYER M2 ;
      RECT 4.995 0.000 5.013 0.054 ;
    END
  END rw0_wd_in[67]
  PIN rw0_wd_in[68]
    DIRECTION INPUT ;
    USE SIGNAL ;
    SHAPE ABUTMENT ;
    PORT
      LAYER M2 ;
      RECT 5.247 0.000 5.265 0.054 ;
    END
  END rw0_wd_in[68]
  PIN rw0_wd_in[69]
    DIRECTION INPUT ;
    USE SIGNAL ;
    SHAPE ABUTMENT ;
    PORT
      LAYER M2 ;
      RECT 5.499 0.000 5.517 0.054 ;
    END
  END rw0_wd_in[69]
  PIN rw0_wd_in[70]
    DIRECTION INPUT ;
    USE SIGNAL ;
    SHAPE ABUTMENT ;
    PORT
      LAYER M2 ;
      RECT 5.751 0.000 5.769 0.054 ;
    END
  END rw0_wd_in[70]
  PIN rw0_wd_in[71]
    DIRECTION INPUT ;
    USE SIGNAL ;
    SHAPE ABUTMENT ;
    PORT
      LAYER M2 ;
      RECT 6.003 0.000 6.021 0.054 ;
    END
  END rw0_wd_in[71]
  PIN rw0_wd_in[72]
    DIRECTION INPUT ;
    USE SIGNAL ;
    SHAPE ABUTMENT ;
    PORT
      LAYER M2 ;
      RECT 6.255 0.000 6.273 0.054 ;
    END
  END rw0_wd_in[72]
  PIN rw0_wd_in[73]
    DIRECTION INPUT ;
    USE SIGNAL ;
    SHAPE ABUTMENT ;
    PORT
      LAYER M2 ;
      RECT 6.507 0.000 6.525 0.054 ;
    END
  END rw0_wd_in[73]
  PIN rw0_wd_in[74]
    DIRECTION INPUT ;
    USE SIGNAL ;
    SHAPE ABUTMENT ;
    PORT
      LAYER M2 ;
      RECT 6.759 0.000 6.777 0.054 ;
    END
  END rw0_wd_in[74]
  PIN rw0_wd_in[75]
    DIRECTION INPUT ;
    USE SIGNAL ;
    SHAPE ABUTMENT ;
    PORT
      LAYER M2 ;
      RECT 7.011 0.000 7.029 0.054 ;
    END
  END rw0_wd_in[75]
  PIN rw0_wd_in[76]
    DIRECTION INPUT ;
    USE SIGNAL ;
    SHAPE ABUTMENT ;
    PORT
      LAYER M2 ;
      RECT 7.263 0.000 7.281 0.054 ;
    END
  END rw0_wd_in[76]
  PIN rw0_wd_in[77]
    DIRECTION INPUT ;
    USE SIGNAL ;
    SHAPE ABUTMENT ;
    PORT
      LAYER M2 ;
      RECT 7.515 0.000 7.533 0.054 ;
    END
  END rw0_wd_in[77]
  PIN rw0_wd_in[78]
    DIRECTION INPUT ;
    USE SIGNAL ;
    SHAPE ABUTMENT ;
    PORT
      LAYER M2 ;
      RECT 7.767 0.000 7.785 0.054 ;
    END
  END rw0_wd_in[78]
  PIN rw0_wd_in[79]
    DIRECTION INPUT ;
    USE SIGNAL ;
    SHAPE ABUTMENT ;
    PORT
      LAYER M2 ;
      RECT 8.019 0.000 8.037 0.054 ;
    END
  END rw0_wd_in[79]
  PIN rw0_wd_in[80]
    DIRECTION INPUT ;
    USE SIGNAL ;
    SHAPE ABUTMENT ;
    PORT
      LAYER M2 ;
      RECT 8.271 0.000 8.289 0.054 ;
    END
  END rw0_wd_in[80]
  PIN rw0_wd_in[81]
    DIRECTION INPUT ;
    USE SIGNAL ;
    SHAPE ABUTMENT ;
    PORT
      LAYER M2 ;
      RECT 8.523 0.000 8.541 0.054 ;
    END
  END rw0_wd_in[81]
  PIN rw0_wd_in[82]
    DIRECTION INPUT ;
    USE SIGNAL ;
    SHAPE ABUTMENT ;
    PORT
      LAYER M2 ;
      RECT 8.775 0.000 8.793 0.054 ;
    END
  END rw0_wd_in[82]
  PIN rw0_wd_in[83]
    DIRECTION INPUT ;
    USE SIGNAL ;
    SHAPE ABUTMENT ;
    PORT
      LAYER M2 ;
      RECT 9.027 0.000 9.045 0.054 ;
    END
  END rw0_wd_in[83]
  PIN rw0_wd_in[84]
    DIRECTION INPUT ;
    USE SIGNAL ;
    SHAPE ABUTMENT ;
    PORT
      LAYER M2 ;
      RECT 9.279 0.000 9.297 0.054 ;
    END
  END rw0_wd_in[84]
  PIN rw0_wd_in[85]
    DIRECTION INPUT ;
    USE SIGNAL ;
    SHAPE ABUTMENT ;
    PORT
      LAYER M2 ;
      RECT 9.531 0.000 9.549 0.054 ;
    END
  END rw0_wd_in[85]
  PIN rw0_wd_in[86]
    DIRECTION INPUT ;
    USE SIGNAL ;
    SHAPE ABUTMENT ;
    PORT
      LAYER M2 ;
      RECT 9.783 0.000 9.801 0.054 ;
    END
  END rw0_wd_in[86]
  PIN rw0_wd_in[87]
    DIRECTION INPUT ;
    USE SIGNAL ;
    SHAPE ABUTMENT ;
    PORT
      LAYER M2 ;
      RECT 10.035 0.000 10.053 0.054 ;
    END
  END rw0_wd_in[87]
  PIN rw0_wd_in[88]
    DIRECTION INPUT ;
    USE SIGNAL ;
    SHAPE ABUTMENT ;
    PORT
      LAYER M2 ;
      RECT 10.287 0.000 10.305 0.054 ;
    END
  END rw0_wd_in[88]
  PIN rw0_wd_in[89]
    DIRECTION INPUT ;
    USE SIGNAL ;
    SHAPE ABUTMENT ;
    PORT
      LAYER M2 ;
      RECT 10.539 0.000 10.557 0.054 ;
    END
  END rw0_wd_in[89]
  PIN rw0_wd_in[90]
    DIRECTION INPUT ;
    USE SIGNAL ;
    SHAPE ABUTMENT ;
    PORT
      LAYER M2 ;
      RECT 10.791 0.000 10.809 0.054 ;
    END
  END rw0_wd_in[90]
  PIN rw0_wd_in[91]
    DIRECTION INPUT ;
    USE SIGNAL ;
    SHAPE ABUTMENT ;
    PORT
      LAYER M2 ;
      RECT 11.043 0.000 11.061 0.054 ;
    END
  END rw0_wd_in[91]
  PIN rw0_wd_in[92]
    DIRECTION INPUT ;
    USE SIGNAL ;
    SHAPE ABUTMENT ;
    PORT
      LAYER M2 ;
      RECT 11.295 0.000 11.313 0.054 ;
    END
  END rw0_wd_in[92]
  PIN rw0_wd_in[93]
    DIRECTION INPUT ;
    USE SIGNAL ;
    SHAPE ABUTMENT ;
    PORT
      LAYER M2 ;
      RECT 11.547 0.000 11.565 0.054 ;
    END
  END rw0_wd_in[93]
  PIN rw0_wd_in[94]
    DIRECTION INPUT ;
    USE SIGNAL ;
    SHAPE ABUTMENT ;
    PORT
      LAYER M2 ;
      RECT 11.799 0.000 11.817 0.054 ;
    END
  END rw0_wd_in[94]
  PIN rw0_wd_in[95]
    DIRECTION INPUT ;
    USE SIGNAL ;
    SHAPE ABUTMENT ;
    PORT
      LAYER M2 ;
      RECT 12.051 0.000 12.069 0.054 ;
    END
  END rw0_wd_in[95]
  PIN rw0_rd_out[0]
    DIRECTION OUTPUT ;
    USE SIGNAL ;
    SHAPE ABUTMENT ;
    PORT
      LAYER M2 ;
      RECT 12.303 0.000 12.321 0.054 ;
    END
  END rw0_rd_out[0]
  PIN rw0_rd_out[1]
    DIRECTION OUTPUT ;
    USE SIGNAL ;
    SHAPE ABUTMENT ;
    PORT
      LAYER M2 ;
      RECT 12.555 0.000 12.573 0.054 ;
    END
  END rw0_rd_out[1]
  PIN rw0_rd_out[2]
    DIRECTION OUTPUT ;
    USE SIGNAL ;
    SHAPE ABUTMENT ;
    PORT
      LAYER M2 ;
      RECT 12.807 0.000 12.825 0.054 ;
    END
  END rw0_rd_out[2]
  PIN rw0_rd_out[3]
    DIRECTION OUTPUT ;
    USE SIGNAL ;
    SHAPE ABUTMENT ;
    PORT
      LAYER M2 ;
      RECT 13.059 0.000 13.077 0.054 ;
    END
  END rw0_rd_out[3]
  PIN rw0_rd_out[4]
    DIRECTION OUTPUT ;
    USE SIGNAL ;
    SHAPE ABUTMENT ;
    PORT
      LAYER M2 ;
      RECT 13.311 0.000 13.329 0.054 ;
    END
  END rw0_rd_out[4]
  PIN rw0_rd_out[5]
    DIRECTION OUTPUT ;
    USE SIGNAL ;
    SHAPE ABUTMENT ;
    PORT
      LAYER M2 ;
      RECT 13.563 0.000 13.581 0.054 ;
    END
  END rw0_rd_out[5]
  PIN rw0_rd_out[6]
    DIRECTION OUTPUT ;
    USE SIGNAL ;
    SHAPE ABUTMENT ;
    PORT
      LAYER M2 ;
      RECT 13.815 0.000 13.833 0.054 ;
    END
  END rw0_rd_out[6]
  PIN rw0_rd_out[7]
    DIRECTION OUTPUT ;
    USE SIGNAL ;
    SHAPE ABUTMENT ;
    PORT
      LAYER M2 ;
      RECT 14.067 0.000 14.085 0.054 ;
    END
  END rw0_rd_out[7]
  PIN rw0_rd_out[8]
    DIRECTION OUTPUT ;
    USE SIGNAL ;
    SHAPE ABUTMENT ;
    PORT
      LAYER M2 ;
      RECT 14.319 0.000 14.337 0.054 ;
    END
  END rw0_rd_out[8]
  PIN rw0_rd_out[9]
    DIRECTION OUTPUT ;
    USE SIGNAL ;
    SHAPE ABUTMENT ;
    PORT
      LAYER M2 ;
      RECT 14.571 0.000 14.589 0.054 ;
    END
  END rw0_rd_out[9]
  PIN rw0_rd_out[10]
    DIRECTION OUTPUT ;
    USE SIGNAL ;
    SHAPE ABUTMENT ;
    PORT
      LAYER M2 ;
      RECT 14.823 0.000 14.841 0.054 ;
    END
  END rw0_rd_out[10]
  PIN rw0_rd_out[11]
    DIRECTION OUTPUT ;
    USE SIGNAL ;
    SHAPE ABUTMENT ;
    PORT
      LAYER M2 ;
      RECT 15.075 0.000 15.093 0.054 ;
    END
  END rw0_rd_out[11]
  PIN rw0_rd_out[12]
    DIRECTION OUTPUT ;
    USE SIGNAL ;
    SHAPE ABUTMENT ;
    PORT
      LAYER M2 ;
      RECT 15.327 0.000 15.345 0.054 ;
    END
  END rw0_rd_out[12]
  PIN rw0_rd_out[13]
    DIRECTION OUTPUT ;
    USE SIGNAL ;
    SHAPE ABUTMENT ;
    PORT
      LAYER M2 ;
      RECT 15.579 0.000 15.597 0.054 ;
    END
  END rw0_rd_out[13]
  PIN rw0_rd_out[14]
    DIRECTION OUTPUT ;
    USE SIGNAL ;
    SHAPE ABUTMENT ;
    PORT
      LAYER M2 ;
      RECT 15.831 0.000 15.849 0.054 ;
    END
  END rw0_rd_out[14]
  PIN rw0_rd_out[15]
    DIRECTION OUTPUT ;
    USE SIGNAL ;
    SHAPE ABUTMENT ;
    PORT
      LAYER M2 ;
      RECT 16.083 0.000 16.101 0.054 ;
    END
  END rw0_rd_out[15]
  PIN rw0_rd_out[16]
    DIRECTION OUTPUT ;
    USE SIGNAL ;
    SHAPE ABUTMENT ;
    PORT
      LAYER M2 ;
      RECT 16.335 0.000 16.353 0.054 ;
    END
  END rw0_rd_out[16]
  PIN rw0_rd_out[17]
    DIRECTION OUTPUT ;
    USE SIGNAL ;
    SHAPE ABUTMENT ;
    PORT
      LAYER M2 ;
      RECT 16.587 0.000 16.605 0.054 ;
    END
  END rw0_rd_out[17]
  PIN rw0_rd_out[18]
    DIRECTION OUTPUT ;
    USE SIGNAL ;
    SHAPE ABUTMENT ;
    PORT
      LAYER M2 ;
      RECT 16.839 0.000 16.857 0.054 ;
    END
  END rw0_rd_out[18]
  PIN rw0_rd_out[19]
    DIRECTION OUTPUT ;
    USE SIGNAL ;
    SHAPE ABUTMENT ;
    PORT
      LAYER M2 ;
      RECT 17.091 0.000 17.109 0.054 ;
    END
  END rw0_rd_out[19]
  PIN rw0_rd_out[20]
    DIRECTION OUTPUT ;
    USE SIGNAL ;
    SHAPE ABUTMENT ;
    PORT
      LAYER M2 ;
      RECT 17.343 0.000 17.361 0.054 ;
    END
  END rw0_rd_out[20]
  PIN rw0_rd_out[21]
    DIRECTION OUTPUT ;
    USE SIGNAL ;
    SHAPE ABUTMENT ;
    PORT
      LAYER M2 ;
      RECT 17.595 0.000 17.613 0.054 ;
    END
  END rw0_rd_out[21]
  PIN rw0_rd_out[22]
    DIRECTION OUTPUT ;
    USE SIGNAL ;
    SHAPE ABUTMENT ;
    PORT
      LAYER M2 ;
      RECT 17.847 0.000 17.865 0.054 ;
    END
  END rw0_rd_out[22]
  PIN rw0_rd_out[23]
    DIRECTION OUTPUT ;
    USE SIGNAL ;
    SHAPE ABUTMENT ;
    PORT
      LAYER M2 ;
      RECT 18.099 0.000 18.117 0.054 ;
    END
  END rw0_rd_out[23]
  PIN rw0_rd_out[24]
    DIRECTION OUTPUT ;
    USE SIGNAL ;
    SHAPE ABUTMENT ;
    PORT
      LAYER M2 ;
      RECT 18.351 0.000 18.369 0.054 ;
    END
  END rw0_rd_out[24]
  PIN rw0_rd_out[25]
    DIRECTION OUTPUT ;
    USE SIGNAL ;
    SHAPE ABUTMENT ;
    PORT
      LAYER M2 ;
      RECT 18.603 0.000 18.621 0.054 ;
    END
  END rw0_rd_out[25]
  PIN rw0_rd_out[26]
    DIRECTION OUTPUT ;
    USE SIGNAL ;
    SHAPE ABUTMENT ;
    PORT
      LAYER M2 ;
      RECT 18.855 0.000 18.873 0.054 ;
    END
  END rw0_rd_out[26]
  PIN rw0_rd_out[27]
    DIRECTION OUTPUT ;
    USE SIGNAL ;
    SHAPE ABUTMENT ;
    PORT
      LAYER M2 ;
      RECT 19.107 0.000 19.125 0.054 ;
    END
  END rw0_rd_out[27]
  PIN rw0_rd_out[28]
    DIRECTION OUTPUT ;
    USE SIGNAL ;
    SHAPE ABUTMENT ;
    PORT
      LAYER M2 ;
      RECT 19.359 0.000 19.377 0.054 ;
    END
  END rw0_rd_out[28]
  PIN rw0_rd_out[29]
    DIRECTION OUTPUT ;
    USE SIGNAL ;
    SHAPE ABUTMENT ;
    PORT
      LAYER M2 ;
      RECT 19.611 0.000 19.629 0.054 ;
    END
  END rw0_rd_out[29]
  PIN rw0_rd_out[30]
    DIRECTION OUTPUT ;
    USE SIGNAL ;
    SHAPE ABUTMENT ;
    PORT
      LAYER M2 ;
      RECT 19.863 0.000 19.881 0.054 ;
    END
  END rw0_rd_out[30]
  PIN rw0_rd_out[31]
    DIRECTION OUTPUT ;
    USE SIGNAL ;
    SHAPE ABUTMENT ;
    PORT
      LAYER M2 ;
      RECT 20.115 0.000 20.133 0.054 ;
    END
  END rw0_rd_out[31]
  PIN rw0_rd_out[32]
    DIRECTION OUTPUT ;
    USE SIGNAL ;
    SHAPE ABUTMENT ;
    PORT
      LAYER M2 ;
      RECT 20.367 0.000 20.385 0.054 ;
    END
  END rw0_rd_out[32]
  PIN rw0_rd_out[33]
    DIRECTION OUTPUT ;
    USE SIGNAL ;
    SHAPE ABUTMENT ;
    PORT
      LAYER M2 ;
      RECT 20.619 0.000 20.637 0.054 ;
    END
  END rw0_rd_out[33]
  PIN rw0_rd_out[34]
    DIRECTION OUTPUT ;
    USE SIGNAL ;
    SHAPE ABUTMENT ;
    PORT
      LAYER M2 ;
      RECT 20.871 0.000 20.889 0.054 ;
    END
  END rw0_rd_out[34]
  PIN rw0_rd_out[35]
    DIRECTION OUTPUT ;
    USE SIGNAL ;
    SHAPE ABUTMENT ;
    PORT
      LAYER M2 ;
      RECT 21.123 0.000 21.141 0.054 ;
    END
  END rw0_rd_out[35]
  PIN rw0_rd_out[36]
    DIRECTION OUTPUT ;
    USE SIGNAL ;
    SHAPE ABUTMENT ;
    PORT
      LAYER M2 ;
      RECT 21.375 0.000 21.393 0.054 ;
    END
  END rw0_rd_out[36]
  PIN rw0_rd_out[37]
    DIRECTION OUTPUT ;
    USE SIGNAL ;
    SHAPE ABUTMENT ;
    PORT
      LAYER M2 ;
      RECT 21.627 0.000 21.645 0.054 ;
    END
  END rw0_rd_out[37]
  PIN rw0_rd_out[38]
    DIRECTION OUTPUT ;
    USE SIGNAL ;
    SHAPE ABUTMENT ;
    PORT
      LAYER M2 ;
      RECT 21.879 0.000 21.897 0.054 ;
    END
  END rw0_rd_out[38]
  PIN rw0_rd_out[39]
    DIRECTION OUTPUT ;
    USE SIGNAL ;
    SHAPE ABUTMENT ;
    PORT
      LAYER M2 ;
      RECT 22.131 0.000 22.149 0.054 ;
    END
  END rw0_rd_out[39]
  PIN rw0_rd_out[40]
    DIRECTION OUTPUT ;
    USE SIGNAL ;
    SHAPE ABUTMENT ;
    PORT
      LAYER M2 ;
      RECT 22.383 0.000 22.401 0.054 ;
    END
  END rw0_rd_out[40]
  PIN rw0_rd_out[41]
    DIRECTION OUTPUT ;
    USE SIGNAL ;
    SHAPE ABUTMENT ;
    PORT
      LAYER M2 ;
      RECT 22.635 0.000 22.653 0.054 ;
    END
  END rw0_rd_out[41]
  PIN rw0_rd_out[42]
    DIRECTION OUTPUT ;
    USE SIGNAL ;
    SHAPE ABUTMENT ;
    PORT
      LAYER M2 ;
      RECT 22.887 0.000 22.905 0.054 ;
    END
  END rw0_rd_out[42]
  PIN rw0_rd_out[43]
    DIRECTION OUTPUT ;
    USE SIGNAL ;
    SHAPE ABUTMENT ;
    PORT
      LAYER M2 ;
      RECT 23.139 0.000 23.157 0.054 ;
    END
  END rw0_rd_out[43]
  PIN rw0_rd_out[44]
    DIRECTION OUTPUT ;
    USE SIGNAL ;
    SHAPE ABUTMENT ;
    PORT
      LAYER M2 ;
      RECT 23.391 0.000 23.409 0.054 ;
    END
  END rw0_rd_out[44]
  PIN rw0_rd_out[45]
    DIRECTION OUTPUT ;
    USE SIGNAL ;
    SHAPE ABUTMENT ;
    PORT
      LAYER M2 ;
      RECT 23.643 0.000 23.661 0.054 ;
    END
  END rw0_rd_out[45]
  PIN rw0_rd_out[46]
    DIRECTION OUTPUT ;
    USE SIGNAL ;
    SHAPE ABUTMENT ;
    PORT
      LAYER M2 ;
      RECT 23.895 0.000 23.913 0.054 ;
    END
  END rw0_rd_out[46]
  PIN rw0_rd_out[47]
    DIRECTION OUTPUT ;
    USE SIGNAL ;
    SHAPE ABUTMENT ;
    PORT
      LAYER M2 ;
      RECT 24.147 0.000 24.165 0.054 ;
    END
  END rw0_rd_out[47]
  PIN rw0_rd_out[48]
    DIRECTION OUTPUT ;
    USE SIGNAL ;
    SHAPE ABUTMENT ;
    PORT
      LAYER M2 ;
      RECT 12.303 9.427 12.321 9.481 ;
    END
  END rw0_rd_out[48]
  PIN rw0_rd_out[49]
    DIRECTION OUTPUT ;
    USE SIGNAL ;
    SHAPE ABUTMENT ;
    PORT
      LAYER M2 ;
      RECT 12.555 9.427 12.573 9.481 ;
    END
  END rw0_rd_out[49]
  PIN rw0_rd_out[50]
    DIRECTION OUTPUT ;
    USE SIGNAL ;
    SHAPE ABUTMENT ;
    PORT
      LAYER M2 ;
      RECT 12.807 9.427 12.825 9.481 ;
    END
  END rw0_rd_out[50]
  PIN rw0_rd_out[51]
    DIRECTION OUTPUT ;
    USE SIGNAL ;
    SHAPE ABUTMENT ;
    PORT
      LAYER M2 ;
      RECT 13.059 9.427 13.077 9.481 ;
    END
  END rw0_rd_out[51]
  PIN rw0_rd_out[52]
    DIRECTION OUTPUT ;
    USE SIGNAL ;
    SHAPE ABUTMENT ;
    PORT
      LAYER M2 ;
      RECT 13.311 9.427 13.329 9.481 ;
    END
  END rw0_rd_out[52]
  PIN rw0_rd_out[53]
    DIRECTION OUTPUT ;
    USE SIGNAL ;
    SHAPE ABUTMENT ;
    PORT
      LAYER M2 ;
      RECT 13.563 9.427 13.581 9.481 ;
    END
  END rw0_rd_out[53]
  PIN rw0_rd_out[54]
    DIRECTION OUTPUT ;
    USE SIGNAL ;
    SHAPE ABUTMENT ;
    PORT
      LAYER M2 ;
      RECT 13.815 9.427 13.833 9.481 ;
    END
  END rw0_rd_out[54]
  PIN rw0_rd_out[55]
    DIRECTION OUTPUT ;
    USE SIGNAL ;
    SHAPE ABUTMENT ;
    PORT
      LAYER M2 ;
      RECT 14.067 9.427 14.085 9.481 ;
    END
  END rw0_rd_out[55]
  PIN rw0_rd_out[56]
    DIRECTION OUTPUT ;
    USE SIGNAL ;
    SHAPE ABUTMENT ;
    PORT
      LAYER M2 ;
      RECT 14.319 9.427 14.337 9.481 ;
    END
  END rw0_rd_out[56]
  PIN rw0_rd_out[57]
    DIRECTION OUTPUT ;
    USE SIGNAL ;
    SHAPE ABUTMENT ;
    PORT
      LAYER M2 ;
      RECT 14.571 9.427 14.589 9.481 ;
    END
  END rw0_rd_out[57]
  PIN rw0_rd_out[58]
    DIRECTION OUTPUT ;
    USE SIGNAL ;
    SHAPE ABUTMENT ;
    PORT
      LAYER M2 ;
      RECT 14.823 9.427 14.841 9.481 ;
    END
  END rw0_rd_out[58]
  PIN rw0_rd_out[59]
    DIRECTION OUTPUT ;
    USE SIGNAL ;
    SHAPE ABUTMENT ;
    PORT
      LAYER M2 ;
      RECT 15.075 9.427 15.093 9.481 ;
    END
  END rw0_rd_out[59]
  PIN rw0_rd_out[60]
    DIRECTION OUTPUT ;
    USE SIGNAL ;
    SHAPE ABUTMENT ;
    PORT
      LAYER M2 ;
      RECT 15.327 9.427 15.345 9.481 ;
    END
  END rw0_rd_out[60]
  PIN rw0_rd_out[61]
    DIRECTION OUTPUT ;
    USE SIGNAL ;
    SHAPE ABUTMENT ;
    PORT
      LAYER M2 ;
      RECT 15.579 9.427 15.597 9.481 ;
    END
  END rw0_rd_out[61]
  PIN rw0_rd_out[62]
    DIRECTION OUTPUT ;
    USE SIGNAL ;
    SHAPE ABUTMENT ;
    PORT
      LAYER M2 ;
      RECT 15.831 9.427 15.849 9.481 ;
    END
  END rw0_rd_out[62]
  PIN rw0_rd_out[63]
    DIRECTION OUTPUT ;
    USE SIGNAL ;
    SHAPE ABUTMENT ;
    PORT
      LAYER M2 ;
      RECT 16.083 9.427 16.101 9.481 ;
    END
  END rw0_rd_out[63]
  PIN rw0_rd_out[64]
    DIRECTION OUTPUT ;
    USE SIGNAL ;
    SHAPE ABUTMENT ;
    PORT
      LAYER M2 ;
      RECT 16.335 9.427 16.353 9.481 ;
    END
  END rw0_rd_out[64]
  PIN rw0_rd_out[65]
    DIRECTION OUTPUT ;
    USE SIGNAL ;
    SHAPE ABUTMENT ;
    PORT
      LAYER M2 ;
      RECT 16.587 9.427 16.605 9.481 ;
    END
  END rw0_rd_out[65]
  PIN rw0_rd_out[66]
    DIRECTION OUTPUT ;
    USE SIGNAL ;
    SHAPE ABUTMENT ;
    PORT
      LAYER M2 ;
      RECT 16.839 9.427 16.857 9.481 ;
    END
  END rw0_rd_out[66]
  PIN rw0_rd_out[67]
    DIRECTION OUTPUT ;
    USE SIGNAL ;
    SHAPE ABUTMENT ;
    PORT
      LAYER M2 ;
      RECT 17.091 9.427 17.109 9.481 ;
    END
  END rw0_rd_out[67]
  PIN rw0_rd_out[68]
    DIRECTION OUTPUT ;
    USE SIGNAL ;
    SHAPE ABUTMENT ;
    PORT
      LAYER M2 ;
      RECT 17.343 9.427 17.361 9.481 ;
    END
  END rw0_rd_out[68]
  PIN rw0_rd_out[69]
    DIRECTION OUTPUT ;
    USE SIGNAL ;
    SHAPE ABUTMENT ;
    PORT
      LAYER M2 ;
      RECT 17.595 9.427 17.613 9.481 ;
    END
  END rw0_rd_out[69]
  PIN rw0_rd_out[70]
    DIRECTION OUTPUT ;
    USE SIGNAL ;
    SHAPE ABUTMENT ;
    PORT
      LAYER M2 ;
      RECT 17.847 9.427 17.865 9.481 ;
    END
  END rw0_rd_out[70]
  PIN rw0_rd_out[71]
    DIRECTION OUTPUT ;
    USE SIGNAL ;
    SHAPE ABUTMENT ;
    PORT
      LAYER M2 ;
      RECT 18.099 9.427 18.117 9.481 ;
    END
  END rw0_rd_out[71]
  PIN rw0_rd_out[72]
    DIRECTION OUTPUT ;
    USE SIGNAL ;
    SHAPE ABUTMENT ;
    PORT
      LAYER M2 ;
      RECT 18.351 9.427 18.369 9.481 ;
    END
  END rw0_rd_out[72]
  PIN rw0_rd_out[73]
    DIRECTION OUTPUT ;
    USE SIGNAL ;
    SHAPE ABUTMENT ;
    PORT
      LAYER M2 ;
      RECT 18.603 9.427 18.621 9.481 ;
    END
  END rw0_rd_out[73]
  PIN rw0_rd_out[74]
    DIRECTION OUTPUT ;
    USE SIGNAL ;
    SHAPE ABUTMENT ;
    PORT
      LAYER M2 ;
      RECT 18.855 9.427 18.873 9.481 ;
    END
  END rw0_rd_out[74]
  PIN rw0_rd_out[75]
    DIRECTION OUTPUT ;
    USE SIGNAL ;
    SHAPE ABUTMENT ;
    PORT
      LAYER M2 ;
      RECT 19.107 9.427 19.125 9.481 ;
    END
  END rw0_rd_out[75]
  PIN rw0_rd_out[76]
    DIRECTION OUTPUT ;
    USE SIGNAL ;
    SHAPE ABUTMENT ;
    PORT
      LAYER M2 ;
      RECT 19.359 9.427 19.377 9.481 ;
    END
  END rw0_rd_out[76]
  PIN rw0_rd_out[77]
    DIRECTION OUTPUT ;
    USE SIGNAL ;
    SHAPE ABUTMENT ;
    PORT
      LAYER M2 ;
      RECT 19.611 9.427 19.629 9.481 ;
    END
  END rw0_rd_out[77]
  PIN rw0_rd_out[78]
    DIRECTION OUTPUT ;
    USE SIGNAL ;
    SHAPE ABUTMENT ;
    PORT
      LAYER M2 ;
      RECT 19.863 9.427 19.881 9.481 ;
    END
  END rw0_rd_out[78]
  PIN rw0_rd_out[79]
    DIRECTION OUTPUT ;
    USE SIGNAL ;
    SHAPE ABUTMENT ;
    PORT
      LAYER M2 ;
      RECT 20.115 9.427 20.133 9.481 ;
    END
  END rw0_rd_out[79]
  PIN rw0_rd_out[80]
    DIRECTION OUTPUT ;
    USE SIGNAL ;
    SHAPE ABUTMENT ;
    PORT
      LAYER M2 ;
      RECT 20.367 9.427 20.385 9.481 ;
    END
  END rw0_rd_out[80]
  PIN rw0_rd_out[81]
    DIRECTION OUTPUT ;
    USE SIGNAL ;
    SHAPE ABUTMENT ;
    PORT
      LAYER M2 ;
      RECT 20.619 9.427 20.637 9.481 ;
    END
  END rw0_rd_out[81]
  PIN rw0_rd_out[82]
    DIRECTION OUTPUT ;
    USE SIGNAL ;
    SHAPE ABUTMENT ;
    PORT
      LAYER M2 ;
      RECT 20.871 9.427 20.889 9.481 ;
    END
  END rw0_rd_out[82]
  PIN rw0_rd_out[83]
    DIRECTION OUTPUT ;
    USE SIGNAL ;
    SHAPE ABUTMENT ;
    PORT
      LAYER M2 ;
      RECT 21.123 9.427 21.141 9.481 ;
    END
  END rw0_rd_out[83]
  PIN rw0_rd_out[84]
    DIRECTION OUTPUT ;
    USE SIGNAL ;
    SHAPE ABUTMENT ;
    PORT
      LAYER M2 ;
      RECT 21.375 9.427 21.393 9.481 ;
    END
  END rw0_rd_out[84]
  PIN rw0_rd_out[85]
    DIRECTION OUTPUT ;
    USE SIGNAL ;
    SHAPE ABUTMENT ;
    PORT
      LAYER M2 ;
      RECT 21.627 9.427 21.645 9.481 ;
    END
  END rw0_rd_out[85]
  PIN rw0_rd_out[86]
    DIRECTION OUTPUT ;
    USE SIGNAL ;
    SHAPE ABUTMENT ;
    PORT
      LAYER M2 ;
      RECT 21.879 9.427 21.897 9.481 ;
    END
  END rw0_rd_out[86]
  PIN rw0_rd_out[87]
    DIRECTION OUTPUT ;
    USE SIGNAL ;
    SHAPE ABUTMENT ;
    PORT
      LAYER M2 ;
      RECT 22.131 9.427 22.149 9.481 ;
    END
  END rw0_rd_out[87]
  PIN rw0_rd_out[88]
    DIRECTION OUTPUT ;
    USE SIGNAL ;
    SHAPE ABUTMENT ;
    PORT
      LAYER M2 ;
      RECT 22.383 9.427 22.401 9.481 ;
    END
  END rw0_rd_out[88]
  PIN rw0_rd_out[89]
    DIRECTION OUTPUT ;
    USE SIGNAL ;
    SHAPE ABUTMENT ;
    PORT
      LAYER M2 ;
      RECT 22.635 9.427 22.653 9.481 ;
    END
  END rw0_rd_out[89]
  PIN rw0_rd_out[90]
    DIRECTION OUTPUT ;
    USE SIGNAL ;
    SHAPE ABUTMENT ;
    PORT
      LAYER M2 ;
      RECT 22.887 9.427 22.905 9.481 ;
    END
  END rw0_rd_out[90]
  PIN rw0_rd_out[91]
    DIRECTION OUTPUT ;
    USE SIGNAL ;
    SHAPE ABUTMENT ;
    PORT
      LAYER M2 ;
      RECT 23.139 9.427 23.157 9.481 ;
    END
  END rw0_rd_out[91]
  PIN rw0_rd_out[92]
    DIRECTION OUTPUT ;
    USE SIGNAL ;
    SHAPE ABUTMENT ;
    PORT
      LAYER M2 ;
      RECT 23.391 9.427 23.409 9.481 ;
    END
  END rw0_rd_out[92]
  PIN rw0_rd_out[93]
    DIRECTION OUTPUT ;
    USE SIGNAL ;
    SHAPE ABUTMENT ;
    PORT
      LAYER M2 ;
      RECT 23.643 9.427 23.661 9.481 ;
    END
  END rw0_rd_out[93]
  PIN rw0_rd_out[94]
    DIRECTION OUTPUT ;
    USE SIGNAL ;
    SHAPE ABUTMENT ;
    PORT
      LAYER M2 ;
      RECT 23.895 9.427 23.913 9.481 ;
    END
  END rw0_rd_out[94]
  PIN rw0_rd_out[95]
    DIRECTION OUTPUT ;
    USE SIGNAL ;
    SHAPE ABUTMENT ;
    PORT
      LAYER M2 ;
      RECT 24.147 9.427 24.165 9.481 ;
    END
  END rw0_rd_out[95]
  PIN rw0_addr_in[0]
    DIRECTION INPUT ;
    USE SIGNAL ;
    SHAPE ABUTMENT ;
    PORT
      LAYER M3 ;
      RECT 0.000 7.188 0.072 7.212 ;
    END
  END rw0_addr_in[0]
  PIN rw0_addr_in[1]
    DIRECTION INPUT ;
    USE SIGNAL ;
    SHAPE ABUTMENT ;
    PORT
      LAYER M3 ;
      RECT 0.000 7.332 0.072 7.356 ;
    END
  END rw0_addr_in[1]
  PIN rw0_addr_in[2]
    DIRECTION INPUT ;
    USE SIGNAL ;
    SHAPE ABUTMENT ;
    PORT
      LAYER M3 ;
      RECT 0.000 7.476 0.072 7.500 ;
    END
  END rw0_addr_in[2]
  PIN rw0_addr_in[3]
    DIRECTION INPUT ;
    USE SIGNAL ;
    SHAPE ABUTMENT ;
    PORT
      LAYER M3 ;
      RECT 25.931 7.188 26.003 7.212 ;
    END
  END rw0_addr_in[3]
  PIN rw0_addr_in[4]
    DIRECTION INPUT ;
    USE SIGNAL ;
    SHAPE ABUTMENT ;
    PORT
      LAYER M3 ;
      RECT 25.931 7.332 26.003 7.356 ;
    END
  END rw0_addr_in[4]
  PIN rw0_addr_in[5]
    DIRECTION INPUT ;
    USE SIGNAL ;
    SHAPE ABUTMENT ;
    PORT
      LAYER M3 ;
      RECT 25.931 7.476 26.003 7.500 ;
    END
  END rw0_addr_in[5]
  PIN rw0_we_in
    DIRECTION INPUT ;
    USE SIGNAL ;
    SHAPE ABUTMENT ;
    PORT
      LAYER M2 ;
      RECT 24.399 9.427 24.417 9.481 ;
    END
  END rw0_we_in
  PIN rw0_ce_in
    DIRECTION INPUT ;
    USE SIGNAL ;
    SHAPE ABUTMENT ;
    PORT
      LAYER M2 ;
      RECT 24.651 9.427 24.669 9.481 ;
    END
  END rw0_ce_in
  PIN rw0_clk
    DIRECTION INPUT ;
    USE SIGNAL ;
    SHAPE ABUTMENT ;
    PORT
      LAYER M2 ;
      RECT 24.903 9.427 24.921 9.481 ;
    END
  END rw0_clk
  PIN VSS
    DIRECTION INOUT ;
    USE GROUND ;
    PORT
      LAYER M4 ;
      RECT 0.168 0.288 0.264 9.193 ;
      RECT 0.936 0.288 1.032 9.193 ;
      RECT 1.704 0.288 1.800 9.193 ;
      RECT 2.472 0.288 2.568 9.193 ;
      RECT 3.240 0.288 3.336 9.193 ;
      RECT 4.008 0.288 4.104 9.193 ;
      RECT 4.776 0.288 4.872 9.193 ;
      RECT 5.544 0.288 5.640 9.193 ;
      RECT 6.312 0.288 6.408 9.193 ;
      RECT 7.080 0.288 7.176 9.193 ;
      RECT 7.848 0.288 7.944 9.193 ;
      RECT 8.616 0.288 8.712 9.193 ;
      RECT 9.384 0.288 9.480 9.193 ;
      RECT 10.152 0.288 10.248 9.193 ;
      RECT 10.920 0.288 11.016 9.193 ;
      RECT 11.688 0.288 11.784 9.193 ;
      RECT 12.456 0.288 12.552 9.193 ;
      RECT 13.224 0.288 13.320 9.193 ;
      RECT 13.992 0.288 14.088 9.193 ;
      RECT 14.760 0.288 14.856 9.193 ;
      RECT 15.528 0.288 15.624 9.193 ;
      RECT 16.296 0.288 16.392 9.193 ;
      RECT 17.064 0.288 17.160 9.193 ;
      RECT 17.832 0.288 17.928 9.193 ;
      RECT 18.600 0.288 18.696 9.193 ;
      RECT 19.368 0.288 19.464 9.193 ;
      RECT 20.136 0.288 20.232 9.193 ;
      RECT 20.904 0.288 21.000 9.193 ;
      RECT 21.672 0.288 21.768 9.193 ;
      RECT 22.440 0.288 22.536 9.193 ;
      RECT 23.208 0.288 23.304 9.193 ;
      RECT 23.976 0.288 24.072 9.193 ;
      RECT 24.744 0.288 24.840 9.193 ;
      RECT 25.512 0.288 25.608 9.193 ;
    END
  END VSS
  PIN VDD
    DIRECTION INOUT ;
    USE POWER ;
    PORT
      LAYER M4 ;
      RECT 0.168 0.288 0.264 9.193 ;
      RECT 0.936 0.288 1.032 9.193 ;
      RECT 1.704 0.288 1.800 9.193 ;
      RECT 2.472 0.288 2.568 9.193 ;
      RECT 3.240 0.288 3.336 9.193 ;
      RECT 4.008 0.288 4.104 9.193 ;
      RECT 4.776 0.288 4.872 9.193 ;
      RECT 5.544 0.288 5.640 9.193 ;
      RECT 6.312 0.288 6.408 9.193 ;
      RECT 7.080 0.288 7.176 9.193 ;
      RECT 7.848 0.288 7.944 9.193 ;
      RECT 8.616 0.288 8.712 9.193 ;
      RECT 9.384 0.288 9.480 9.193 ;
      RECT 10.152 0.288 10.248 9.193 ;
      RECT 10.920 0.288 11.016 9.193 ;
      RECT 11.688 0.288 11.784 9.193 ;
      RECT 12.456 0.288 12.552 9.193 ;
      RECT 13.224 0.288 13.320 9.193 ;
      RECT 13.992 0.288 14.088 9.193 ;
      RECT 14.760 0.288 14.856 9.193 ;
      RECT 15.528 0.288 15.624 9.193 ;
      RECT 16.296 0.288 16.392 9.193 ;
      RECT 17.064 0.288 17.160 9.193 ;
      RECT 17.832 0.288 17.928 9.193 ;
      RECT 18.600 0.288 18.696 9.193 ;
      RECT 19.368 0.288 19.464 9.193 ;
      RECT 20.136 0.288 20.232 9.193 ;
      RECT 20.904 0.288 21.000 9.193 ;
      RECT 21.672 0.288 21.768 9.193 ;
      RECT 22.440 0.288 22.536 9.193 ;
      RECT 23.208 0.288 23.304 9.193 ;
      RECT 23.976 0.288 24.072 9.193 ;
      RECT 24.744 0.288 24.840 9.193 ;
      RECT 25.512 0.288 25.608 9.193 ;
    END
  END VDD
  OBS
    LAYER M1 ;
    RECT 0 0 26.003 9.481 ;
    LAYER M2 ;
    RECT 0 0 26.003 9.481 ;
    LAYER M3 ;
    RECT 0 0 26.003 9.481 ;
    LAYER M4 ;
    RECT 0 0 26.003 9.481 ;
  END
END ht_asap7_blackparrot_64x96_bottom

END LIBRARY
